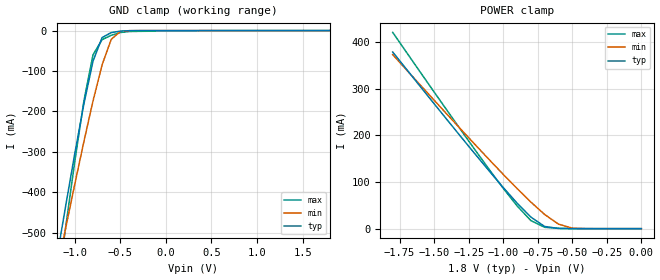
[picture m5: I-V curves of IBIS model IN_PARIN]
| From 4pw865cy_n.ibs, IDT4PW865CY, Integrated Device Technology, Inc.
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|   Model IN_PARIN
[Model]   IN_PARIN
Model_type   Input
Vinl =  0.000V
Vinh =  1.80000V
C_comp   3.00000pF   3.0000pF   3.00000pF
[Temperature Range]   25.00000   0.11000k   0.000
[Voltage Range]   1.80000V   1.70000V   1.90000V
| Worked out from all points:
|   GND clamp passes 1 mA (typ) near -0.47 V on its own axis
|   POWER clamp passes 1 mA (typ) near -0.61 V on its own axis
[GND_clamp]
| voltage   I(typ)   I(min)   I(max)
-1.8V     -1.393A    -1.281A    -1.7A
-1.2V     -567.3mA   -599.7mA   -654.5mA
-1.1V     -434.2mA   -489.2mA   -486.7mA
-1V       -304.7mA   -380.5mA   -324.5mA
-900mV    -181.9mA   -274.8mA   -174.3mA
-800mV    -75.82mA   -174.4mA   -60.04mA
-700mV    -17.21mA   -84.69mA   -22.44mA
-600mV    -4.993mA   -21.66mA   -11.64mA
-500mV    -1.257mA   -2.2mA     -4.858mA
-400mV    -291.9uA   -246uA     -2.288mA
300mV     7.762nA    555pA      -466.4uA
1.8V      79.32nA    28.7nA     15.06nA
[POWER_clamp]
| voltage   I(typ)   I(min)   I(max)
-1.8V     378.3mA    372.7mA    420.3mA
-1.4V     230.9mA    242.8mA    250.5mA
-1.1V     123mA      147.4mA    126.2mA
-900mV    54.91mA    86.07mA    48.97mA
-800mV    24.9mA     57.02mA    17.34mA
-700mV    4.699mA    30.42mA    2.893mA
-600mV    377.5uA    9.667mA    728.2uA
-500mV    44.93uA    1.061mA    142.1uA
0V        79.32nA    13.29nA    16.46nA
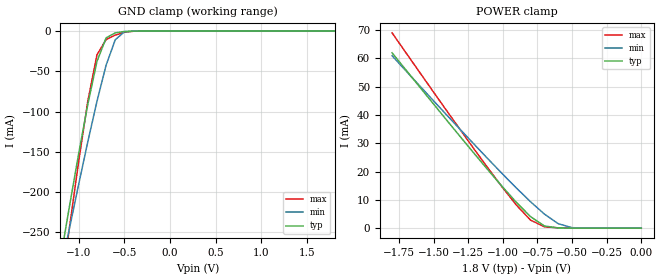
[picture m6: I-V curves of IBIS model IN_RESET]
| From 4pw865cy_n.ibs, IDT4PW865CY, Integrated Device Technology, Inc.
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|   Model IN_RESET
[Model]   IN_RESET
Model_type   Input
Vinl =  0.59500V
Vinh =  1.23500V
C_comp   3.00000pF   3.0000pF   3.00000pF
[Temperature Range]   25.00000   0.11000k   0.000
[Voltage Range]   1.80000V   1.70000V   1.90000V
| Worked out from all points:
|   GND clamp passes 1 mA (typ) near -0.53 V on its own axis
|   POWER clamp passes 1 mA (typ) near -0.71 V on its own axis
[GND_clamp]
| voltage   I(typ)   I(min)   I(max)
-1.8V     -696mA     -640mA     -849.2mA
-1.2V     -283.2mA   -299.5mA   -326.6mA
-1.1V     -216.7mA   -244.3mA   -242.7mA
-1V       -151.9mA   -190mA     -161.6mA
-900mV    -90.6mA    -137.2mA   -86.5mA
-800mV    -37.6mA    -87.02mA   -29.37mA
-700mV    -8.34mA    -42.2mA    -10.49mA
-600mV    -2.267mA   -10.7mA    -4.974mA
-500mV    -443.3uA   -979.6uA   -1.485mA
-300mV    -1.495uA   -2.695uA   -7.139uA
1.8V      19.45pA    2.948nA    -3.682pA
[POWER_clamp]
| voltage   I(typ)   I(min)   I(max)
-1.8V     61.94mA    60.89mA    68.97mA
-1.4V     37.81mA    39.68mA    41.1mA
-1.1V     20.14mA    24.09mA    20.72mA
-900mV    8.997mA    14.08mA    8.037mA
-800mV    4.08mA     9.329mA    2.846mA
-700mV    769.7uA    4.978mA    477.8uA
-600mV    62.43uA    1.579mA    121.3uA
-500mV    7.465uA    173uA      23.68uA
0V        19.45pA    399.5pA    5.95pA
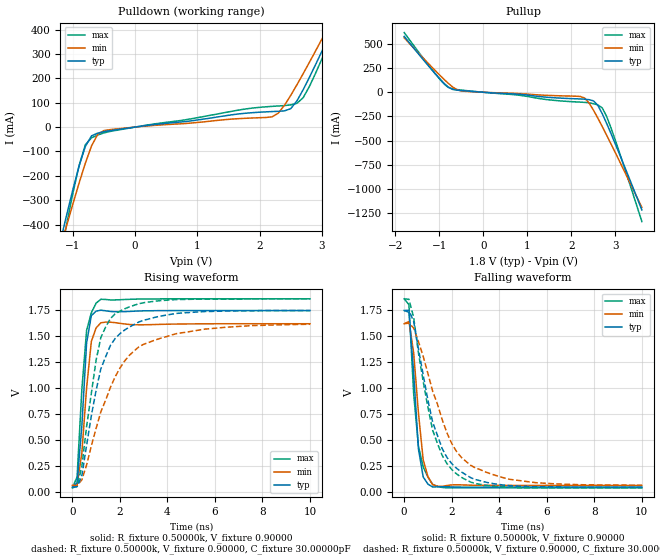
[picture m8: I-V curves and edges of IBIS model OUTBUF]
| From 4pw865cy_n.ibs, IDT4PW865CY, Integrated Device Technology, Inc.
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|   Model OUTBUF
[Model]   OUTBUF
Model_type   Output
Polarity   Inverting
C_comp   6.50000pF   8.10000pF   5.40000pF
[Temperature Range]   25.00000   0.11000k   0.000
[Voltage Range]   1.80000V   1.70000V   1.90000V
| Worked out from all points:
|   slope of the pulldown table from 0 to 0.27 V, typ, clamps not added: 29.7 ohm
|   slope of the pullup table from 0 to 0.27 V, typ, clamps not added: 35.5 ohm
|   rising waveform, R_fixture 0.50000k, V_fixture 0.90000: 20-80 % time 285ps typ, 337ps min, 317ps max; typ from 0.047 V to 1.74 V
|   rising waveform, R_fixture 0.50000k, V_fixture 0.90000, C_fixture 30.00000pF: 20-80 % time 1.04ns typ, 1.63ns min, 734ps max; typ from 0.047 V to 1.74 V
|   falling waveform, R_fixture 0.50000k, V_fixture 0.90000: 20-80 % time 310ps typ, 360ps min, 366ps max; typ from 1.74 V to 0.047 V
|   falling waveform, R_fixture 0.50000k, V_fixture 0.90000, C_fixture 30.00000pF: 20-80 % time 1.09ns typ, 1.46ns min, 1ns max; typ from 1.74 V to 0.047 V
[Pulldown]
| voltage   I(typ)   I(min)   I(max)
-1.8V     -1.143A    -1.055A    -1.369A
-1.2V     -468.2mA   -494.8mA   -530.4mA
-1.1V     -360.3mA   -404.2mA   -397.3mA
-900mV    -159.4mA   -229.2mA   -157.4mA
-700mV    -35.92mA   -76.98mA   -43.85mA
-500mV    -18.76mA   -14.23mA   -23.74mA
2.2V      63.59mA    42.02mA    84.92mA
2.5V      75.54mA    130.3mA    91.16mA
2.7V      153.8mA    219.6mA    120.8mA
3.1V      365.6mA    409.3mA    339.1mA
3.2V      420.6mA    457.7mA    399.4mA
3.6V      644mA      653.4mA    645.2mA
[Pullup]
| voltage   I(typ)   I(min)   I(max)
-1.8V     578.2mA    563.7mA    617.9mA
-1.1V     194.8mA    226.9mA    195.6mA
-800mV    54.3mA     93.4mA     50.68mA
-500mV    17.9mA     13.27mA    22.79mA
2.2V      -69.15mA   -43.16mA   -102mA
2.3V      -71.44mA   -59.77mA   -104.5mA
2.5V      -88.71mA   -184.8mA   -118.1mA
2.6V      -135.6mA   -267.6mA   -130.6mA
2.7V      -221.9mA   -354.8mA   -161.6mA
2.8V      -322.5mA   -444.4mA   -250.7mA
3V        -538.4mA   -627.8mA   -501mA
3.6V      -1.218A    -1.192A    -1.338A
[Ramp]
| variable   typ   min   max
dV/dt_r   0.59832/0.23639n   0.47454/0.32567n   0.72720/0.22250n
dV/dt_f   0.63180/0.24820n   0.48774/0.35166n   0.74052/0.26520n
R_load = 50.00000
[Rising Waveform]
R_fixture = 0.50000k
V_fixture = 0.90000
V_fixture_min = 0.85000
V_fixture_max = 0.95000
| time   V(typ)   V(min)   V(max)
0s        46.99mV    63.92mV    40.56mV
200ps     90.67mV    69.03mV    145mV
400ps     635mV      374.6mV    984.7mV
600ps     1.432V     1V         1.552V
800ps     1.695V     1.447V     1.723V
1ns       1.738V     1.577V     1.815V
1.2ns     1.747V     1.626V     1.852V
1.8ns     1.732V     1.627V     1.846V
2.8ns     1.74V      1.607V     1.854V
10ns      1.744V     1.617V     1.856V
[Rising Waveform]
R_fixture = 0.50000k
V_fixture = 0.90000
V_fixture_min = 0.85000
V_fixture_max = 0.95000
C_fixture = 30.00000pF
| time   V(typ)   V(min)   V(max)
0s        46.99mV    63.92mV    40.56mV
200ps     51.47mV    62.58mV    54.76mV
400ps     156.5mV    116.7mV    246.5mV
600ps     448.7mV    260.5mV    629mV
1ns       977.4mV    611.9mV    1.267V
1.2ns     1.184V     771.3mV    1.485V
1.8ns     1.475V     1.107V     1.712V
2.8ns     1.634V     1.395V     1.81V
4.4ns     1.716V     1.523V     1.849V
10ns      1.744V     1.612V     1.856V
[Falling Waveform]
R_fixture = 0.50000k
V_fixture = 0.90000
V_fixture_min = 0.85000
V_fixture_max = 0.95000
| time   V(typ)   V(min)   V(max)
0s        1.744V     1.617V     1.856V
200ps     1.727V     1.639V     1.8V
400ps     1.139V     1.337V     941.9mV
600ps     413.1mV    759.5mV    441.7mV
800ps     145.3mV    309mV      241.7mV
1ns       75.85mV    147.7mV    142.7mV
1.2ns     48.46mV    70.43mV    73.02mV
1.4ns     50.03mV    54.5mV     55.27mV
1.8ns     50.76mV    62.94mV    40.9mV
10ns      46.99mV    63.92mV    40.56mV
[Falling Waveform]
R_fixture = 0.50000k
V_fixture = 0.90000
V_fixture_min = 0.85000
V_fixture_max = 0.95000
C_fixture = 30.00000pF
| time   V(typ)   V(min)   V(max)
0s        1.744V     1.617V     1.856V
200ps     1.746V     1.623V     1.851V
400ps     1.639V     1.575V     1.677V
800ps     1.125V     1.304V     1.062V
1.2ns     669.6mV    967.1mV    592.7mV
1.6ns     417mV      694.9mV    351.4mV
2.2ns     229.2mV    390.3mV    174.8mV
3ns       119.9mV    231.4mV    81.81mV
4.4ns     61.59mV    123.7mV    45.84mV
10ns      47.02mV    64.87mV    40.56mV
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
